VERSION 5.7 ;
  NOWIREEXTENSIONATPIN ON ;
  DIVIDERCHAR "/" ;
  BUSBITCHARS "[]" ;
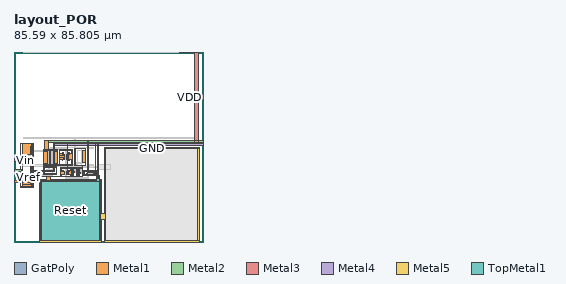
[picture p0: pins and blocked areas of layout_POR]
MACRO layout_POR
  CLASS BLOCK ;
  FOREIGN layout_POR ;
  ORIGIN 26.975 33.135 ;
  SIZE 85.590 BY 85.805 ;
  PIN VDD
    USE POWER ;
    PORT
      LAYER GatPoly ;
        RECT 47.765 52.240 49.765 52.670 ;
        RECT 49.965 52.240 51.965 52.670 ;
        RECT 52.165 52.240 54.165 52.670 ;
        RECT 54.365 52.240 56.365 52.670 ;
        RECT -12.725 7.775 -12.425 8.075 ;
        RECT -12.555 7.665 -12.425 7.775 ;
        RECT -8.475 7.775 -8.175 8.075 ;
        RECT -8.475 7.665 -8.345 7.775 ;
        RECT -5.105 6.810 -4.805 7.110 ;
        RECT -2.275 6.810 -1.975 7.110 ;
        RECT -5.020 6.540 -4.890 6.810 ;
        RECT -2.190 6.540 -2.060 6.810 ;
        RECT -5.020 3.760 -4.890 3.940 ;
        RECT -2.190 3.760 -2.060 3.940 ;
        RECT -12.555 2.285 -12.425 2.465 ;
        RECT -8.475 2.285 -8.345 2.465 ;
      LAYER Metal1 ;
        RECT 47.785 52.370 56.345 52.670 ;
        RECT -13.410 8.615 -11.480 12.585 ;
        RECT 54.395 11.935 56.325 12.555 ;
        RECT -13.655 8.315 -7.255 8.615 ;
        RECT -13.655 8.005 -13.355 8.315 ;
        RECT -7.555 8.005 -7.255 8.315 ;
        RECT -13.655 7.665 -12.425 8.005 ;
        RECT -8.475 7.665 -7.255 8.005 ;
        RECT -13.655 2.465 -11.645 7.665 ;
        RECT -10.900 2.465 -10.625 7.665 ;
        RECT -9.255 2.465 -7.255 7.665 ;
        RECT -13.655 1.815 -13.355 2.465 ;
        RECT -10.900 1.815 -10.740 2.465 ;
        RECT -7.555 1.865 -7.255 2.465 ;
        RECT -6.605 8.265 -0.605 8.565 ;
        RECT -6.605 7.050 -6.305 8.265 ;
        RECT -0.905 7.050 -0.605 8.265 ;
        RECT -6.605 5.800 -4.620 7.050 ;
        RECT -4.130 5.800 -3.970 6.540 ;
        RECT -6.605 4.895 -3.970 5.800 ;
        RECT -6.605 3.950 -4.620 4.895 ;
        RECT -6.605 1.865 -6.305 3.950 ;
        RECT -5.290 3.940 -5.130 3.950 ;
        RECT -4.780 3.940 -4.620 3.950 ;
        RECT -4.130 3.940 -3.970 4.895 ;
        RECT -2.460 3.950 -0.605 7.050 ;
        RECT -2.460 3.940 -2.300 3.950 ;
        RECT -1.950 3.940 -1.790 3.950 ;
        RECT -0.905 1.865 -0.605 3.950 ;
        RECT -7.555 1.815 -0.605 1.865 ;
        RECT -13.655 1.565 -0.605 1.815 ;
        RECT -13.655 1.515 -7.255 1.565 ;
        RECT -13.655 0.910 -13.355 1.515 ;
        RECT -13.655 0.610 -7.655 0.910 ;
        RECT -13.655 -2.290 -13.355 0.610 ;
        RECT -7.955 -2.290 -7.655 0.610 ;
        RECT 6.225 -1.750 8.975 -1.725 ;
        RECT 6.125 -1.910 9.075 -1.750 ;
        RECT 6.225 -1.935 8.975 -1.910 ;
        RECT -13.655 -2.590 -7.655 -2.290 ;
      LAYER Metal2 ;
        RECT 54.400 52.415 56.330 52.615 ;
        RECT -13.410 11.830 58.615 12.655 ;
        RECT 6.225 -1.930 8.975 -1.730 ;
      LAYER Metal3 ;
        RECT 6.225 -1.730 6.445 12.655 ;
        RECT 54.380 11.830 56.345 52.615 ;
        RECT 6.225 -1.930 8.975 -1.730 ;
        RECT 6.225 -1.935 6.445 -1.930 ;
    END
  END VDD
  PIN Vin
    ANTENNAGATEAREA 13.467999 ;
    PORT
      LAYER GatPoly ;
        RECT -23.155 4.280 -22.975 5.610 ;
        RECT -23.435 3.300 -22.975 4.280 ;
        RECT -23.155 1.910 -22.975 3.300 ;
        RECT -19.335 1.910 -19.155 5.610 ;
      LAYER Metal1 ;
        RECT -23.390 3.235 -23.180 4.345 ;
      LAYER Metal2 ;
        RECT -26.970 3.240 -23.160 4.355 ;
        RECT -23.385 3.235 -23.185 3.240 ;
    END
  END Vin
  PIN Vref
    ANTENNAGATEAREA 13.467999 ;
    PORT
      LAYER GatPoly ;
        RECT -23.155 -0.460 -22.975 1.020 ;
        RECT -23.435 -1.440 -22.975 -0.460 ;
        RECT -23.155 -2.680 -22.975 -1.440 ;
        RECT -19.335 -2.680 -19.155 1.020 ;
      LAYER Metal1 ;
        RECT -23.390 -1.505 -23.180 -0.395 ;
      LAYER Metal2 ;
        RECT -26.970 -1.510 -23.160 -0.395 ;
    END
  END Vref
  PIN GND
    ANTENNAGATEAREA 27.274000 ;
    ANTENNADIFFAREA 48.882698 ;
    PORT
      LAYER GatPoly ;
        RECT -23.155 6.500 -22.975 10.200 ;
        RECT -19.335 10.080 -19.155 10.200 ;
        RECT -19.335 9.100 -18.855 10.080 ;
        RECT -19.335 6.500 -19.155 9.100 ;
        RECT -5.175 -0.945 -4.875 -0.645 ;
        RECT -2.115 -0.945 -1.815 -0.645 ;
        RECT -5.090 -1.215 -4.960 -0.945 ;
        RECT -2.030 -1.215 -1.900 -0.945 ;
        RECT -5.090 -2.695 -4.960 -2.515 ;
        RECT -2.030 -2.695 -1.900 -2.515 ;
        RECT -23.155 -7.270 -22.975 -3.570 ;
        RECT -19.335 -6.155 -19.155 -3.570 ;
        RECT -19.335 -7.135 -18.855 -6.155 ;
        RECT -19.335 -7.270 -19.155 -7.135 ;
      LAYER Metal1 ;
        RECT -24.155 11.165 -18.155 11.465 ;
        RECT -24.155 -5.235 -23.855 11.165 ;
        RECT -23.155 6.230 -18.900 11.165 ;
        RECT -26.975 -6.350 -23.855 -5.235 ;
        RECT -24.155 -8.235 -23.855 -6.350 ;
        RECT -23.155 -6.090 -18.905 -3.300 ;
        RECT -18.455 -3.335 -18.155 11.165 ;
        RECT 0.435 8.895 5.435 9.195 ;
        RECT 0.435 1.495 0.735 8.895 ;
        RECT 5.135 8.045 5.435 8.895 ;
        RECT 4.070 2.745 5.435 8.045 ;
        RECT 5.135 1.495 5.435 2.745 ;
        RECT 0.435 1.195 5.435 1.495 ;
        RECT 3.855 0.365 4.160 1.195 ;
        RECT -5.965 0.065 4.160 0.365 ;
        RECT -5.965 -0.715 -5.665 0.065 ;
        RECT -1.265 -0.715 -0.965 0.065 ;
        RECT -12.075 -0.950 -9.325 -0.925 ;
        RECT -12.195 -1.110 -9.245 -0.950 ;
        RECT -12.075 -1.135 -9.325 -1.110 ;
        RECT -5.965 -1.215 -4.690 -0.715 ;
        RECT -5.965 -2.515 -3.970 -1.215 ;
        RECT -5.965 -2.695 -4.690 -2.515 ;
        RECT -2.300 -2.695 -0.965 -0.715 ;
        RECT -5.965 -3.335 -5.665 -2.695 ;
        RECT -1.265 -3.335 -0.965 -2.695 ;
        RECT -18.455 -3.635 -0.965 -3.335 ;
        RECT -0.360 -1.250 -0.060 0.065 ;
        RECT -0.360 -1.960 0.415 -1.250 ;
        RECT -0.360 -3.335 -0.060 -1.960 ;
        RECT 1.340 -3.335 1.640 0.065 ;
        RECT -0.360 -3.635 1.640 -3.335 ;
        RECT 2.160 -1.580 2.460 0.065 ;
        RECT 2.160 -2.100 2.990 -1.580 ;
        RECT 3.860 -2.045 4.160 0.065 ;
        RECT 4.625 -1.350 10.625 -1.050 ;
        RECT 4.625 -2.045 4.925 -1.350 ;
        RECT 2.160 -3.335 2.460 -2.100 ;
        RECT 3.860 -2.205 4.925 -2.045 ;
        RECT 3.860 -3.335 4.160 -2.205 ;
        RECT 4.625 -2.750 4.925 -2.205 ;
        RECT 10.325 -2.750 10.625 -1.350 ;
        RECT 4.625 -3.050 10.625 -2.750 ;
        RECT 2.160 -3.635 4.160 -3.335 ;
        RECT -23.155 -7.200 -18.900 -6.090 ;
        RECT -23.155 -8.235 -18.905 -7.200 ;
        RECT -18.455 -8.235 -18.155 -3.635 ;
        RECT -12.110 -5.375 -10.590 -3.635 ;
        RECT -24.155 -8.535 -18.155 -8.235 ;
      LAYER Metal2 ;
        RECT -19.105 9.035 -18.905 10.145 ;
        RECT -18.455 -1.135 -9.325 -0.925 ;
        RECT -12.110 -5.370 -10.590 -5.170 ;
        RECT -19.105 -7.200 -18.905 -6.090 ;
      LAYER Metal3 ;
        RECT -12.110 -5.370 -10.590 -5.170 ;
      LAYER Metal4 ;
        RECT -12.110 -5.370 -10.590 -5.170 ;
      LAYER Metal5 ;
        RECT 13.885 8.985 56.605 9.585 ;
        RECT -15.595 -5.555 12.585 -4.955 ;
        RECT -15.595 -32.535 -14.995 -5.555 ;
        RECT 11.985 -20.265 12.585 -5.555 ;
        RECT 13.885 -20.265 14.485 8.985 ;
        RECT 11.985 -23.060 14.485 -20.265 ;
        RECT 11.985 -32.535 12.585 -23.060 ;
        RECT -15.595 -33.135 12.585 -32.535 ;
        RECT 13.885 -32.535 14.485 -23.060 ;
        RECT 56.005 -32.535 56.605 8.985 ;
        RECT 13.885 -33.135 56.605 -32.535 ;
    END
  END GND
  PIN Reset
    ANTENNAGATEAREA 0.767000 ;
    ANTENNADIFFAREA 1.326000 ;
    PORT
      LAYER GatPoly ;
        RECT -8.975 -0.710 -8.675 -0.455 ;
        RECT -12.375 -0.840 -12.195 -0.710 ;
        RECT -9.245 -0.840 -8.675 -0.710 ;
        RECT -8.975 -1.095 -8.675 -0.840 ;
        RECT 9.360 -2.020 10.000 -1.940 ;
        RECT 5.945 -2.150 6.125 -2.020 ;
        RECT 9.075 -2.150 10.000 -2.020 ;
        RECT 9.360 -2.240 10.000 -2.150 ;
      LAYER Metal1 ;
        RECT -3.110 6.455 -2.950 6.540 ;
        RECT -3.135 4.115 -2.925 6.455 ;
        RECT -3.110 3.940 -2.950 4.115 ;
        RECT -8.930 -1.125 -8.720 -0.425 ;
        RECT -3.110 -1.310 -2.950 -1.215 ;
        RECT -3.135 -2.420 -2.925 -1.310 ;
        RECT 9.330 -2.195 10.030 -1.985 ;
        RECT -3.110 -2.515 -2.950 -2.420 ;
      LAYER Metal2 ;
        RECT -3.130 4.115 -2.930 6.455 ;
        RECT -8.975 -1.125 -8.675 -0.425 ;
        RECT -3.130 -2.420 -2.930 -1.310 ;
        RECT 9.330 -2.240 10.030 -1.940 ;
      LAYER Metal3 ;
        RECT -8.930 -0.920 -8.720 11.135 ;
        RECT -2.830 6.455 -2.630 11.135 ;
        RECT -3.130 4.115 -2.630 6.455 ;
        RECT -8.925 -1.125 -8.725 -0.920 ;
        RECT -2.830 -1.310 -2.630 4.115 ;
        RECT -3.130 -2.420 -2.630 -1.310 ;
        RECT 9.615 -1.990 9.925 11.135 ;
        RECT 9.330 -2.190 10.030 -1.990 ;
        RECT 9.615 -2.240 9.925 -2.190 ;
        RECT 10.750 -3.630 11.060 11.125 ;
        RECT 10.555 -4.240 11.255 -3.630 ;
      LAYER Metal4 ;
        RECT -8.930 10.310 58.615 11.135 ;
        RECT 10.555 -4.240 11.255 -3.630 ;
      LAYER Metal5 ;
        RECT 10.555 -4.245 11.255 -3.625 ;
      LAYER TopMetal1 ;
        RECT 10.085 -5.815 11.725 -3.115 ;
        RECT -14.735 -32.275 11.725 -5.815 ;
    END
  END Reset
  OBS
      LAYER GatPoly ;
        RECT -22.635 52.240 -20.635 52.670 ;
        RECT -20.435 52.240 -18.435 52.670 ;
        RECT -18.235 52.240 -16.235 52.670 ;
        RECT -16.035 52.240 -14.035 52.670 ;
        RECT -13.835 52.240 -11.835 52.670 ;
        RECT -11.635 52.240 -9.635 52.670 ;
        RECT -9.435 52.240 -7.435 52.670 ;
        RECT -7.235 52.240 -5.235 52.670 ;
        RECT -5.035 52.240 -3.035 52.670 ;
        RECT -2.835 52.240 -0.835 52.670 ;
        RECT -0.635 52.240 1.365 52.670 ;
        RECT 1.565 52.240 3.565 52.670 ;
        RECT 3.765 52.240 5.765 52.670 ;
        RECT 5.965 52.240 7.965 52.670 ;
        RECT 8.165 52.240 10.165 52.670 ;
        RECT 10.365 52.240 12.365 52.670 ;
        RECT 12.565 52.240 14.565 52.670 ;
        RECT 14.765 52.240 16.765 52.670 ;
        RECT 16.965 52.240 18.965 52.670 ;
        RECT 19.165 52.240 21.165 52.670 ;
        RECT 21.365 52.240 23.365 52.670 ;
        RECT 23.565 52.240 25.565 52.670 ;
        RECT 25.765 52.240 27.765 52.670 ;
        RECT 27.965 52.240 29.965 52.670 ;
        RECT 30.165 52.240 32.165 52.670 ;
        RECT 32.365 52.240 34.365 52.670 ;
        RECT 34.565 52.240 36.565 52.670 ;
        RECT 36.765 52.240 38.765 52.670 ;
        RECT 38.965 52.240 40.965 52.670 ;
        RECT 41.165 52.240 43.165 52.670 ;
        RECT 43.365 52.240 45.365 52.670 ;
        RECT 45.565 52.240 47.565 52.670 ;
        RECT -22.635 13.500 -20.635 13.930 ;
        RECT -20.435 13.500 -18.435 13.930 ;
        RECT -18.235 13.500 -16.235 13.930 ;
        RECT -16.035 13.500 -14.035 13.930 ;
        RECT -13.835 13.500 -11.835 13.930 ;
        RECT -11.635 13.500 -9.635 13.930 ;
        RECT -9.435 13.500 -7.435 13.930 ;
        RECT -7.235 13.500 -5.235 13.930 ;
        RECT -5.035 13.500 -3.035 13.930 ;
        RECT -2.835 13.500 -0.835 13.930 ;
        RECT -0.635 13.500 1.365 13.930 ;
        RECT 1.565 13.500 3.565 13.930 ;
        RECT 3.765 13.500 5.765 13.930 ;
        RECT 5.965 13.500 7.965 13.930 ;
        RECT 8.165 13.500 10.165 13.930 ;
        RECT 10.365 13.500 12.365 13.930 ;
        RECT 12.565 13.500 14.565 13.930 ;
        RECT 14.765 13.500 16.765 13.930 ;
        RECT 16.965 13.500 18.965 13.930 ;
        RECT 19.165 13.500 21.165 13.930 ;
        RECT 21.365 13.500 23.365 13.930 ;
        RECT 23.565 13.500 25.565 13.930 ;
        RECT 25.765 13.500 27.765 13.930 ;
        RECT 27.965 13.500 29.965 13.930 ;
        RECT 30.165 13.500 32.165 13.930 ;
        RECT 32.365 13.500 34.365 13.930 ;
        RECT 34.565 13.500 36.565 13.930 ;
        RECT 36.765 13.500 38.765 13.930 ;
        RECT 38.965 13.500 40.965 13.930 ;
        RECT 41.165 13.500 43.165 13.930 ;
        RECT 43.365 13.500 45.365 13.930 ;
        RECT 45.565 13.500 47.565 13.930 ;
        RECT 47.765 13.500 49.765 13.930 ;
        RECT 49.965 13.500 51.965 13.930 ;
        RECT 52.165 13.500 54.165 13.930 ;
        RECT 54.365 13.500 56.365 13.930 ;
        RECT 7.045 9.255 9.045 9.685 ;
        RECT -11.620 7.845 -11.320 8.145 ;
        RECT -9.580 7.845 -9.280 8.145 ;
        RECT 2.010 8.045 3.960 8.225 ;
        RECT -11.535 7.665 -11.405 7.845 ;
        RECT -10.515 7.665 -10.385 7.845 ;
        RECT -9.495 7.665 -9.365 7.845 ;
        RECT -3.860 6.540 -3.730 6.720 ;
        RECT -3.350 6.540 -3.220 6.720 ;
        RECT -3.860 3.675 -3.730 3.940 ;
        RECT -3.350 3.675 -3.220 3.940 ;
        RECT -3.860 3.375 -3.220 3.675 ;
        RECT 2.010 2.565 3.960 2.745 ;
        RECT -11.535 2.285 -11.405 2.465 ;
        RECT -10.515 2.285 -10.385 2.465 ;
        RECT -9.495 2.285 -9.365 2.465 ;
        RECT 2.155 2.310 3.815 2.565 ;
        RECT -10.515 1.985 -10.215 2.285 ;
        RECT 7.045 1.375 9.045 1.805 ;
        RECT -3.860 -0.970 -3.220 -0.670 ;
        RECT -3.860 -1.215 -3.730 -0.970 ;
        RECT -3.350 -1.215 -3.220 -0.970 ;
        RECT 0.480 -1.060 0.780 -0.420 ;
        RECT 0.555 -1.530 0.705 -1.060 ;
        RECT 2.940 -1.065 3.240 -0.425 ;
        RECT 3.090 -1.445 3.240 -1.065 ;
        RECT 3.100 -1.580 3.230 -1.445 ;
        RECT 0.555 -1.960 0.705 -1.680 ;
        RECT 3.100 -2.280 3.230 -2.100 ;
        RECT -3.860 -2.695 -3.730 -2.515 ;
        RECT -3.350 -2.695 -3.220 -2.515 ;
      LAYER Metal1 ;
        RECT -22.615 52.370 -18.455 52.670 ;
        RECT -18.215 52.370 -14.055 52.670 ;
        RECT -13.815 52.370 -9.655 52.670 ;
        RECT -9.415 52.370 -5.255 52.670 ;
        RECT -5.015 52.370 -0.855 52.670 ;
        RECT -0.615 52.370 3.545 52.670 ;
        RECT 3.785 52.370 7.945 52.670 ;
        RECT 8.185 52.370 12.345 52.670 ;
        RECT 12.585 52.370 16.745 52.670 ;
        RECT 16.985 52.370 21.145 52.670 ;
        RECT 21.385 52.370 25.545 52.670 ;
        RECT 25.785 52.370 29.945 52.670 ;
        RECT 30.185 52.370 34.345 52.670 ;
        RECT 34.585 52.370 38.745 52.670 ;
        RECT 38.985 52.370 43.145 52.670 ;
        RECT 43.385 52.370 47.545 52.670 ;
        RECT -22.615 13.500 -20.655 13.800 ;
        RECT -20.415 13.500 -16.255 13.800 ;
        RECT -16.015 13.500 -11.855 13.800 ;
        RECT -11.615 13.500 -7.455 13.800 ;
        RECT -7.215 13.500 -3.055 13.800 ;
        RECT -2.815 13.500 1.345 13.800 ;
        RECT 1.585 13.500 5.745 13.800 ;
        RECT 5.985 13.500 10.145 13.800 ;
        RECT 10.385 13.500 14.545 13.800 ;
        RECT 14.785 13.500 18.945 13.800 ;
        RECT 19.185 13.500 23.345 13.800 ;
        RECT 23.585 13.500 27.745 13.800 ;
        RECT 27.985 13.500 32.145 13.800 ;
        RECT 32.385 13.500 36.545 13.800 ;
        RECT 36.785 13.500 40.945 13.800 ;
        RECT 41.185 13.500 45.345 13.800 ;
        RECT 45.585 13.500 56.345 13.800 ;
        RECT 7.065 9.385 9.025 9.685 ;
        RECT -11.220 8.075 -9.700 8.105 ;
        RECT -11.600 7.915 -9.300 8.075 ;
        RECT -11.295 7.895 -9.700 7.915 ;
        RECT -22.945 5.880 -19.375 5.900 ;
        RECT -22.975 5.720 -19.335 5.880 ;
        RECT -22.945 5.690 -19.375 5.720 ;
        RECT -11.295 2.465 -11.135 7.895 ;
        RECT 1.740 7.770 1.900 8.045 ;
        RECT -10.300 2.865 -10.090 7.665 ;
        RECT -9.765 7.260 -9.605 7.665 ;
        RECT -10.275 2.465 -10.115 2.865 ;
        RECT -9.790 2.215 -9.580 7.260 ;
        RECT -3.645 4.200 -3.435 6.540 ;
        RECT -3.620 3.940 -3.460 4.200 ;
        RECT -3.890 3.420 -3.190 3.630 ;
        RECT 1.715 2.970 1.925 7.770 ;
        RECT 1.740 2.745 1.900 2.970 ;
        RECT 2.020 2.355 3.950 2.565 ;
        RECT -10.495 2.055 -9.580 2.215 ;
        RECT -9.790 2.050 -9.580 2.055 ;
        RECT -19.355 1.800 -18.735 1.815 ;
        RECT -22.975 1.130 -18.735 1.800 ;
        RECT 7.065 1.375 9.025 1.675 ;
        RECT -19.355 1.115 -18.735 1.130 ;
        RECT -12.015 -0.440 -10.495 -0.415 ;
        RECT -12.195 -0.600 -9.245 -0.440 ;
        RECT -12.015 -0.625 -10.495 -0.600 ;
        RECT -3.890 -0.925 -3.190 -0.715 ;
        RECT 0.525 -0.800 0.735 -0.390 ;
        RECT 0.525 -1.090 1.005 -0.800 ;
        RECT -3.620 -1.330 -3.460 -1.215 ;
        RECT -3.645 -2.440 -3.435 -1.330 ;
        RECT 0.845 -1.960 1.005 -1.090 ;
        RECT 2.985 -1.095 3.195 -0.395 ;
        RECT 3.350 -1.580 3.640 -1.490 ;
        RECT 3.340 -2.100 3.640 -1.580 ;
        RECT 3.350 -2.190 3.640 -2.100 ;
        RECT 6.225 -2.260 8.975 -2.235 ;
        RECT 6.125 -2.420 9.075 -2.260 ;
        RECT -3.620 -2.515 -3.460 -2.440 ;
        RECT 6.225 -2.445 8.975 -2.420 ;
        RECT -22.945 -2.790 -19.375 -2.765 ;
        RECT -22.975 -2.950 -19.335 -2.790 ;
        RECT -22.945 -2.975 -19.375 -2.950 ;
      LAYER Metal2 ;
        RECT -22.590 13.500 1.345 13.800 ;
        RECT -10.295 9.425 9.015 9.640 ;
        RECT -11.435 8.880 -3.435 8.910 ;
        RECT -11.435 8.680 -3.410 8.880 ;
        RECT -11.435 8.660 -3.435 8.680 ;
        RECT -22.940 8.100 -9.700 8.105 ;
        RECT -22.945 7.900 -9.700 8.100 ;
        RECT -22.940 7.895 -9.700 7.900 ;
        RECT -22.945 5.695 -19.375 5.895 ;
        RECT -10.295 2.865 -10.095 7.665 ;
        RECT -9.785 2.050 -9.585 7.260 ;
        RECT -3.640 4.200 -3.440 6.540 ;
        RECT -3.890 3.375 -3.190 3.625 ;
        RECT 1.720 2.970 1.920 7.770 ;
        RECT 0.525 2.560 3.950 2.565 ;
        RECT 0.485 2.360 3.950 2.560 ;
        RECT 0.525 2.355 3.950 2.360 ;
        RECT -19.355 1.110 1.920 1.815 ;
        RECT 7.090 1.425 9.020 1.625 ;
        RECT 11.510 0.860 12.210 1.045 ;
        RECT -3.890 0.660 12.395 0.860 ;
        RECT 11.510 0.435 12.210 0.660 ;
        RECT 15.050 0.435 15.750 1.045 ;
        RECT -12.015 -0.620 -10.495 -0.420 ;
        RECT -3.890 -0.970 -3.190 -0.670 ;
        RECT 0.480 -1.090 0.780 -0.390 ;
        RECT 2.940 -1.095 3.240 -0.395 ;
        RECT -3.640 -2.440 -3.440 -1.330 ;
        RECT 3.430 -2.190 3.640 -1.490 ;
        RECT 6.225 -2.440 8.975 -2.240 ;
        RECT -22.945 -2.770 -9.580 -2.765 ;
        RECT -22.945 -2.970 -9.540 -2.770 ;
        RECT -3.635 -4.375 6.445 -4.175 ;
      LAYER Metal3 ;
        RECT 0.525 13.750 0.735 13.765 ;
        RECT -0.600 13.550 1.330 13.750 ;
        RECT -10.295 9.635 -10.090 9.640 ;
        RECT -10.295 9.435 -10.005 9.635 ;
        RECT -22.940 8.100 -19.375 8.105 ;
        RECT -22.945 7.900 -19.375 8.100 ;
        RECT -22.940 5.895 -19.375 7.900 ;
        RECT -22.945 5.695 -19.375 5.895 ;
        RECT -22.940 5.690 -19.375 5.695 ;
        RECT -11.425 -0.420 -11.035 8.915 ;
        RECT -10.295 2.865 -10.090 9.435 ;
        RECT -3.635 8.880 -3.435 8.925 ;
        RECT -3.700 8.680 -3.410 8.880 ;
        RECT -12.015 -0.620 -10.495 -0.420 ;
        RECT -9.790 -2.770 -9.580 7.470 ;
        RECT -3.635 6.540 -3.435 8.680 ;
        RECT -3.640 5.750 -3.435 6.540 ;
        RECT -3.640 4.200 -3.440 5.750 ;
        RECT -3.890 -0.920 -3.190 3.625 ;
        RECT 0.525 2.560 0.735 13.550 ;
        RECT 3.310 9.605 3.600 9.635 ;
        RECT 3.310 9.435 3.635 9.605 ;
        RECT 0.485 2.360 0.775 2.560 ;
        RECT 0.525 -0.445 0.735 2.360 ;
        RECT 1.720 1.110 1.920 7.975 ;
        RECT 2.990 -0.445 3.190 -0.395 ;
        RECT 0.525 -0.850 3.215 -0.445 ;
        RECT 0.525 -1.090 0.735 -0.850 ;
        RECT 2.990 -1.095 3.190 -0.850 ;
        RECT -9.830 -2.970 -9.540 -2.770 ;
        RECT -3.645 -4.175 -3.435 -1.330 ;
        RECT 3.435 -2.190 3.635 9.435 ;
        RECT 7.090 0.660 9.020 1.625 ;
        RECT 11.510 0.435 12.210 1.045 ;
        RECT 15.050 0.435 15.750 1.045 ;
        RECT 6.225 -2.440 8.975 -2.240 ;
        RECT 6.225 -4.175 6.445 -2.440 ;
        RECT -3.645 -4.375 -3.345 -4.175 ;
        RECT 6.155 -4.375 6.445 -4.175 ;
      LAYER Metal4 ;
        RECT 11.510 0.435 12.210 1.045 ;
        RECT 15.050 0.435 15.750 1.045 ;
      LAYER Metal5 ;
        RECT 11.510 0.430 12.210 1.050 ;
      LAYER TopMetal1 ;
        RECT 10.910 -0.210 12.810 1.690 ;
        RECT 14.450 -32.570 56.030 9.010 ;
      LAYER TopMetal2 ;
        RECT 10.860 -0.260 16.400 1.740 ;
  END
END layout_POR
END LIBRARY

